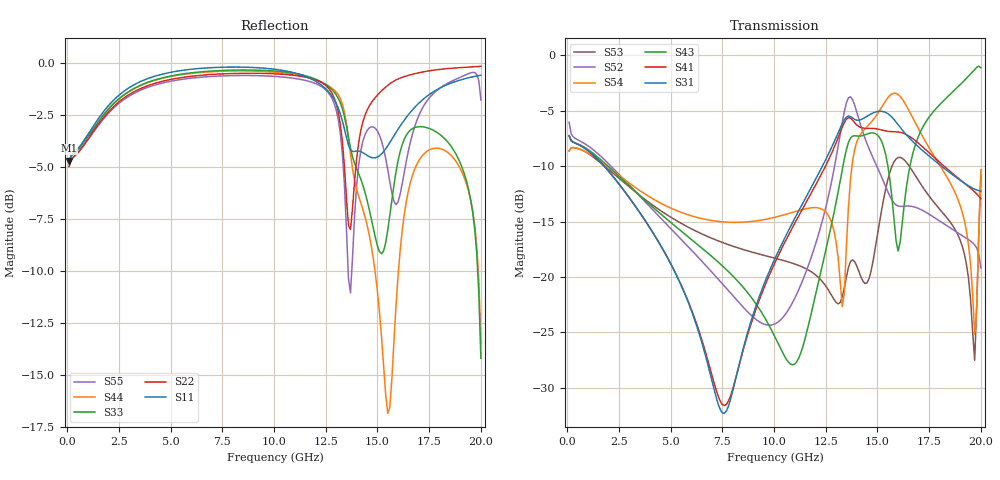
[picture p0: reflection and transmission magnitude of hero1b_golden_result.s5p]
! Created Sat Apr 11 11:04:45 2020
# hz S ma R 50
! freq  magS11  angS11  magS12  angS12  magS13  angS13  magS14  angS14
!  magS15  angS15
!  magS21  angS21  magS22  angS22  magS23  angS23
!  magS24  angS24  magS25  angS25
!  magS31  angS31  magS32  angS32
!  magS33  angS33  magS34  angS34  magS35  angS35
!  magS41  angS41
!  magS42  angS42  magS43  angS43  magS44  angS44  magS45  angS45
!  magS51  angS51  magS52  angS52  magS53  angS53  magS54  angS54
!  magS55  angS55
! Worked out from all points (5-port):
!   200 points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, 100 MHz to 20 GHz, reference 50 ohm
!   strongest paths, dB at 100 MHz, 5.1 GHz, 10.1 GHz, 15.1 GHz, 20 GHz:
!     S31: -7.3, -19.1, -18.1, -5.1, -12.3
!     S41: -7.2, -19.1, -18.5, -6.7, -12.9
!     S43: -7.3, -15.2, -25.6, -7.4, -1.1
!     S54: -8.6, -13.9, -14.6, -5.0, -10.3
!     S52: -6.0, -15.8, -24.2, -10.5, -19.2
!     S53: -8.6, -14.7, -18.3, -15.1, -10.8
!   lowest |S11| = -4.7 dB at 100 MHz (marker M1), VSWR 3.79, Z = 13.3 - j3.41 ohm
!   |S11| at or under -10 dB: nowhere
